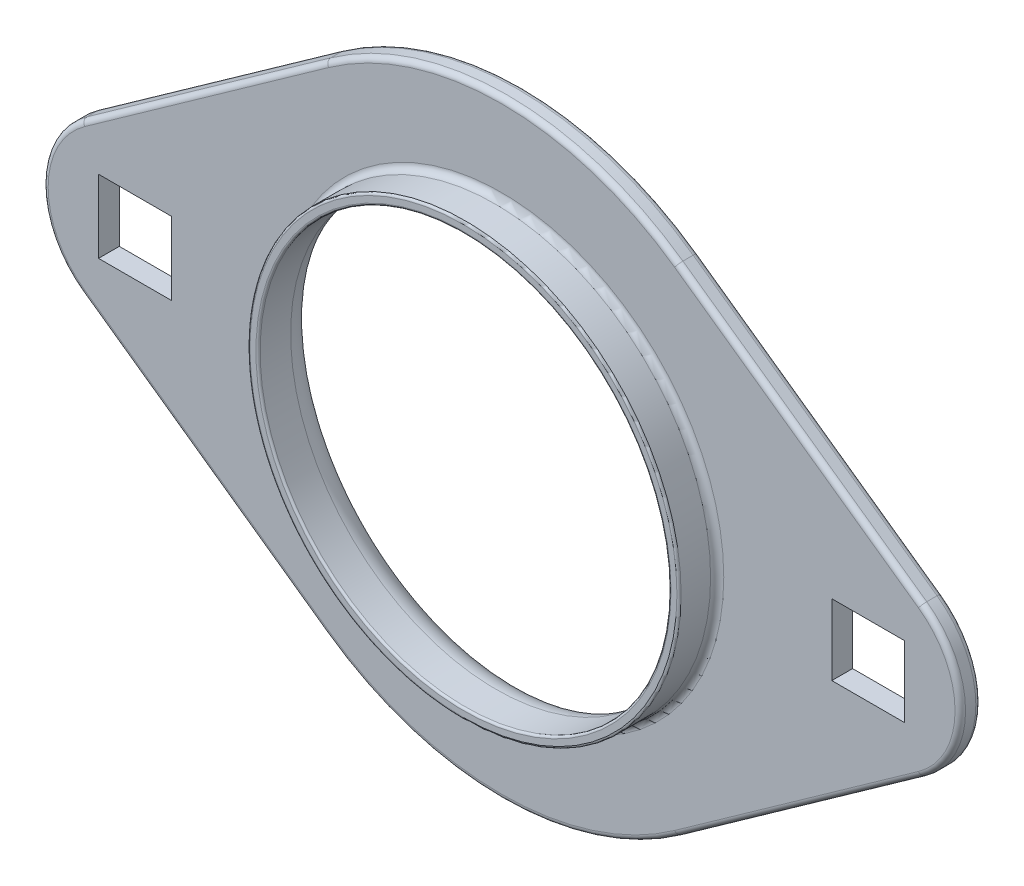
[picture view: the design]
ISO-10303-21;
HEADER;
FILE_DESCRIPTION(('STEP AP214'),'2;1');
FILE_NAME('part.step','',(''),(''),'','','');
FILE_SCHEMA(('AUTOMOTIVE_DESIGN { 1 0 10303 214 1 1 1 1 }'));
ENDSEC;
DATA;
#1=APPLICATION_CONTEXT('core data for automotive mechanical design processes');
#2=APPLICATION_PROTOCOL_DEFINITION('international standard','automotive_design',2000,#1);
#3=PRODUCT_CONTEXT('',#1,'mechanical');
#4=PRODUCT('Part','Part','',(#3));
#5=PRODUCT_RELATED_PRODUCT_CATEGORY('part','',(#4));
#6=PRODUCT_DEFINITION_FORMATION('','',#4);
#7=PRODUCT_DEFINITION_CONTEXT('part definition',#1,'design');
#8=PRODUCT_DEFINITION('design','',#6,#7);
#9=PRODUCT_DEFINITION_SHAPE('','',#8);
#10=(LENGTH_UNIT() NAMED_UNIT(*) SI_UNIT(.MILLI.,.METRE.));
#11=(NAMED_UNIT(*) PLANE_ANGLE_UNIT() SI_UNIT($,.RADIAN.));
#12=(NAMED_UNIT(*) SI_UNIT($,.STERADIAN.) SOLID_ANGLE_UNIT());
#13=UNCERTAINTY_MEASURE_WITH_UNIT(LENGTH_MEASURE(1.E-05),#10,'distance_accuracy_value','');
#14=(GEOMETRIC_REPRESENTATION_CONTEXT(3) GLOBAL_UNCERTAINTY_ASSIGNED_CONTEXT((#13)) GLOBAL_UNIT_ASSIGNED_CONTEXT((#10,
#11,#12)) REPRESENTATION_CONTEXT('',''));
#15=CARTESIAN_POINT('',(0.,0.,0.));
#16=DIRECTION('',(0.,0.,1.));
#17=DIRECTION('',(1.,0.,0.));
#18=AXIS2_PLACEMENT_3D('',#15,#16,#17);
#19=CARTESIAN_POINT('',(0.,0.,1.0033));
#20=DIRECTION('',(0.,0.,1.));
#21=DIRECTION('',(1.,0.,0.));
#22=AXIS2_PLACEMENT_3D('',#19,#20,#21);
#23=PLANE('',#22);
#24=CARTESIAN_POINT('',(35.39871,0.,1.0033));
#25=DIRECTION('',(0.,0.,1.));
#26=DIRECTION('',(1.,0.,0.));
#27=AXIS2_PLACEMENT_3D('',#24,#25,#26);
#28=CIRCLE('',#27,8.38200000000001);
#29=CARTESIAN_POINT('',(40.2493417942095,-6.83588291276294,1.0033));
#30=VERTEX_POINT('',#29);
#31=CARTESIAN_POINT('',(40.2493417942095,6.83588291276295,1.0033));
#32=VERTEX_POINT('',#31);
#33=EDGE_CURVE('E57',#30,#32,#28,.T.);
#34=ORIENTED_EDGE('',*,*,#33,.T.);
#35=DIRECTION('',(-0.81554317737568,0.578696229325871,0.));
#36=VECTOR('',#35,1.);
#37=CARTESIAN_POINT('',(16.7052819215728,23.5423664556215,1.0033));
#38=LINE('',#37,#36);
#39=CARTESIAN_POINT('',(16.7052819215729,23.5423664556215,1.0033));
#40=VERTEX_POINT('',#39);
#41=EDGE_CURVE('E372',#32,#40,#38,.T.);
#42=ORIENTED_EDGE('',*,*,#41,.T.);
#43=CARTESIAN_POINT('',(0.,0.,1.0033));
#44=DIRECTION('',(0.,0.,1.));
#45=DIRECTION('',(1.,0.,0.));
#46=AXIS2_PLACEMENT_3D('',#43,#44,#45);
#47=CIRCLE('',#46,28.8671);
#48=CARTESIAN_POINT('',(-16.7052819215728,23.5423664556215,1.0033));
#49=VERTEX_POINT('',#48);
#50=EDGE_CURVE('E360',#40,#49,#47,.T.);
#51=ORIENTED_EDGE('',*,*,#50,.T.);
#52=DIRECTION('',(-0.81554317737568,-0.578696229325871,0.));
#53=VECTOR('',#52,1.);
#54=CARTESIAN_POINT('',(-40.2493417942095,6.83588291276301,1.0033));
#55=LINE('',#54,#53);
#56=CARTESIAN_POINT('',(-40.2493417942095,6.83588291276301,1.0033));
#57=VERTEX_POINT('',#56);
#58=EDGE_CURVE('E362',#49,#57,#55,.T.);
#59=ORIENTED_EDGE('',*,*,#58,.T.);
#60=CARTESIAN_POINT('',(-35.39871,0.,1.0033));
#61=DIRECTION('',(0.,0.,1.));
#62=DIRECTION('',(1.,0.,0.));
#63=AXIS2_PLACEMENT_3D('',#60,#61,#62);
#64=CIRCLE('',#63,8.382);
#65=CARTESIAN_POINT('',(-40.2493417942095,-6.83588291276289,1.0033));
#66=VERTEX_POINT('',#65);
#67=EDGE_CURVE('E364',#57,#66,#64,.T.);
#68=ORIENTED_EDGE('',*,*,#67,.T.);
#69=DIRECTION('',(0.815543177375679,-0.578696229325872,0.));
#70=VECTOR('',#69,1.);
#71=CARTESIAN_POINT('',(-16.7052819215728,-23.5423664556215,1.0033));
#72=LINE('',#71,#70);
#73=CARTESIAN_POINT('',(-16.7052819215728,-23.5423664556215,1.0033));
#74=VERTEX_POINT('',#73);
#75=EDGE_CURVE('E366',#66,#74,#72,.T.);
#76=ORIENTED_EDGE('',*,*,#75,.T.);
#77=CARTESIAN_POINT('',(0.,0.,1.0033));
#78=DIRECTION('',(0.,0.,1.));
#79=DIRECTION('',(1.,0.,0.));
#80=AXIS2_PLACEMENT_3D('',#77,#78,#79);
#81=CIRCLE('',#80,28.8671);
#82=CARTESIAN_POINT('',(16.7052819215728,-23.5423664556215,1.0033));
#83=VERTEX_POINT('',#82);
#84=EDGE_CURVE('E368',#74,#83,#81,.T.);
#85=ORIENTED_EDGE('',*,*,#84,.T.);
#86=DIRECTION('',(0.81554317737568,0.578696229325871,0.));
#87=VECTOR('',#86,1.);
#88=CARTESIAN_POINT('',(40.2493417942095,-6.83588291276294,1.0033));
#89=LINE('',#88,#87);
#90=EDGE_CURVE('E62',#83,#30,#89,.T.);
#91=ORIENTED_EDGE('',*,*,#90,.T.);
#92=EDGE_LOOP('',(#34,#42,#51,#59,#68,#76,#85,#91));
#93=FACE_BOUND('',#92,.T.);
#94=CARTESIAN_POINT('',(0.,0.,1.0033));
#95=DIRECTION('',(0.,0.,1.));
#96=DIRECTION('',(1.,0.,0.));
#97=AXIS2_PLACEMENT_3D('',#94,#95,#96);
#98=CIRCLE('',#97,21.4503);
#99=CARTESIAN_POINT('',(21.4503,0.,1.0033));
#100=VERTEX_POINT('',#99);
#101=EDGE_CURVE('E310',#100,#100,#98,.F.);
#102=ORIENTED_EDGE('',*,*,#101,.T.);
#103=EDGE_LOOP('',(#102));
#104=FACE_BOUND('',#103,.T.);
#105=DIRECTION('',(1.,0.,0.));
#106=VECTOR('',#105,1.);
#107=CARTESIAN_POINT('',(31.88208,-3.42392,1.0033));
#108=LINE('',#107,#106);
#109=CARTESIAN_POINT('',(31.88208,-3.42392,1.0033));
#110=VERTEX_POINT('',#109);
#111=CARTESIAN_POINT('',(38.91788,-3.42392,1.0033));
#112=VERTEX_POINT('',#111);
#113=EDGE_CURVE('E214',#110,#112,#108,.T.);
#114=ORIENTED_EDGE('',*,*,#113,.F.);
#115=DIRECTION('',(0.,-1.,0.));
#116=VECTOR('',#115,1.);
#117=CARTESIAN_POINT('',(31.88208,3.42392,1.0033));
#118=LINE('',#117,#116);
#119=CARTESIAN_POINT('',(31.88208,3.42392,1.0033));
#120=VERTEX_POINT('',#119);
#121=EDGE_CURVE('E204',#120,#110,#118,.T.);
#122=ORIENTED_EDGE('',*,*,#121,.F.);
#123=DIRECTION('',(-1.,0.,0.));
#124=VECTOR('',#123,1.);
#125=CARTESIAN_POINT('',(31.88208,3.42392,1.0033));
#126=LINE('',#125,#124);
#127=CARTESIAN_POINT('',(38.91788,3.42392,1.0033));
#128=VERTEX_POINT('',#127);
#129=EDGE_CURVE('E230',#128,#120,#126,.T.);
#130=ORIENTED_EDGE('',*,*,#129,.F.);
#131=DIRECTION('',(0.,1.,0.));
#132=VECTOR('',#131,1.);
#133=CARTESIAN_POINT('',(38.91788,3.42392,1.0033));
#134=LINE('',#133,#132);
#135=EDGE_CURVE('E228',#112,#128,#134,.T.);
#136=ORIENTED_EDGE('',*,*,#135,.F.);
#137=EDGE_LOOP('',(#114,#122,#130,#136));
#138=FACE_BOUND('',#137,.T.);
#139=DIRECTION('',(1.,0.,0.));
#140=VECTOR('',#139,1.);
#141=CARTESIAN_POINT('',(-38.91788,-3.5179,1.0033));
#142=LINE('',#141,#140);
#143=CARTESIAN_POINT('',(-38.91788,-3.5179,1.0033));
#144=VERTEX_POINT('',#143);
#145=CARTESIAN_POINT('',(-31.88208,-3.5179,1.0033));
#146=VERTEX_POINT('',#145);
#147=EDGE_CURVE('E249',#144,#146,#142,.T.);
#148=ORIENTED_EDGE('',*,*,#147,.F.);
#149=DIRECTION('',(0.,-1.,0.));
#150=VECTOR('',#149,1.);
#151=CARTESIAN_POINT('',(-38.91788,3.5179,1.0033));
#152=LINE('',#151,#150);
#153=CARTESIAN_POINT('',(-38.91788,3.5179,1.0033));
#154=VERTEX_POINT('',#153);
#155=EDGE_CURVE('E247',#154,#144,#152,.T.);
#156=ORIENTED_EDGE('',*,*,#155,.F.);
#157=DIRECTION('',(-1.,0.,0.));
#158=VECTOR('',#157,1.);
#159=CARTESIAN_POINT('',(-38.91788,3.5179,1.0033));
#160=LINE('',#159,#158);
#161=CARTESIAN_POINT('',(-31.88208,3.5179,1.0033));
#162=VERTEX_POINT('',#161);
#163=EDGE_CURVE('E255',#162,#154,#160,.T.);
#164=ORIENTED_EDGE('',*,*,#163,.F.);
#165=DIRECTION('',(0.,1.,0.));
#166=VECTOR('',#165,1.);
#167=CARTESIAN_POINT('',(-31.88208,3.5179,1.0033));
#168=LINE('',#167,#166);
#169=EDGE_CURVE('E252',#146,#162,#168,.T.);
#170=ORIENTED_EDGE('',*,*,#169,.F.);
#171=EDGE_LOOP('',(#148,#156,#164,#170));
#172=FACE_BOUND('',#171,.T.);
#173=ADVANCED_FACE('F42',(#93,#104,#138,#172),#23,.T.);
#174=CARTESIAN_POINT('',(0.,0.,-1.0033));
#175=DIRECTION('',(0.,0.,1.));
#176=DIRECTION('',(1.,0.,0.));
#177=AXIS2_PLACEMENT_3D('',#174,#175,#176);
#178=PLANE('',#177);
#179=CARTESIAN_POINT('',(0.,0.,-1.0033));
#180=DIRECTION('',(0.,0.,1.));
#181=DIRECTION('',(1.,0.,0.));
#182=AXIS2_PLACEMENT_3D('',#179,#180,#181);
#183=CIRCLE('',#182,28.8671);
#184=CARTESIAN_POINT('',(-16.7052819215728,23.5423664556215,-1.0033));
#185=VERTEX_POINT('',#184);
#186=CARTESIAN_POINT('',(16.7052819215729,23.5423664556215,-1.0033));
#187=VERTEX_POINT('',#186);
#188=EDGE_CURVE('E319',#185,#187,#183,.F.);
#189=ORIENTED_EDGE('',*,*,#188,.T.);
#190=DIRECTION('',(-0.81554317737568,0.578696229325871,0.));
#191=VECTOR('',#190,1.);
#192=CARTESIAN_POINT('',(16.7052819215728,23.5423664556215,-1.0033));
#193=LINE('',#192,#191);
#194=CARTESIAN_POINT('',(40.2493417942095,6.83588291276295,-1.0033));
#195=VERTEX_POINT('',#194);
#196=EDGE_CURVE('E333',#187,#195,#193,.F.);
#197=ORIENTED_EDGE('',*,*,#196,.T.);
#198=CARTESIAN_POINT('',(35.39871,0.,-1.0033));
#199=DIRECTION('',(0.,0.,1.));
#200=DIRECTION('',(1.,0.,0.));
#201=AXIS2_PLACEMENT_3D('',#198,#199,#200);
#202=CIRCLE('',#201,8.38200000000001);
#203=CARTESIAN_POINT('',(40.2493417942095,-6.83588291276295,-1.0033));
#204=VERTEX_POINT('',#203);
#205=EDGE_CURVE('E331',#195,#204,#202,.F.);
#206=ORIENTED_EDGE('',*,*,#205,.T.);
#207=DIRECTION('',(0.81554317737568,0.578696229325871,0.));
#208=VECTOR('',#207,1.);
#209=CARTESIAN_POINT('',(16.7052819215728,-23.5423664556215,-1.0033));
#210=LINE('',#209,#208);
#211=CARTESIAN_POINT('',(16.7052819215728,-23.5423664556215,-1.0033));
#212=VERTEX_POINT('',#211);
#213=EDGE_CURVE('E329',#204,#212,#210,.F.);
#214=ORIENTED_EDGE('',*,*,#213,.T.);
#215=CARTESIAN_POINT('',(0.,0.,-1.0033));
#216=DIRECTION('',(0.,0.,1.));
#217=DIRECTION('',(1.,0.,0.));
#218=AXIS2_PLACEMENT_3D('',#215,#216,#217);
#219=CIRCLE('',#218,28.8671);
#220=CARTESIAN_POINT('',(-16.7052819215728,-23.5423664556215,-1.0033));
#221=VERTEX_POINT('',#220);
#222=EDGE_CURVE('E327',#212,#221,#219,.F.);
#223=ORIENTED_EDGE('',*,*,#222,.T.);
#224=DIRECTION('',(0.815543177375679,-0.578696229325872,0.));
#225=VECTOR('',#224,1.);
#226=CARTESIAN_POINT('',(-16.7052819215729,-23.5423664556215,-1.0033));
#227=LINE('',#226,#225);
#228=CARTESIAN_POINT('',(-40.2493417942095,-6.83588291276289,-1.0033));
#229=VERTEX_POINT('',#228);
#230=EDGE_CURVE('E325',#221,#229,#227,.F.);
#231=ORIENTED_EDGE('',*,*,#230,.T.);
#232=CARTESIAN_POINT('',(-35.39871,0.,-1.0033));
#233=DIRECTION('',(0.,0.,1.));
#234=DIRECTION('',(1.,0.,0.));
#235=AXIS2_PLACEMENT_3D('',#232,#233,#234);
#236=CIRCLE('',#235,8.382);
#237=CARTESIAN_POINT('',(-40.2493417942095,6.83588291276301,-1.0033));
#238=VERTEX_POINT('',#237);
#239=EDGE_CURVE('E323',#229,#238,#236,.F.);
#240=ORIENTED_EDGE('',*,*,#239,.T.);
#241=DIRECTION('',(-0.81554317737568,-0.578696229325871,0.));
#242=VECTOR('',#241,1.);
#243=CARTESIAN_POINT('',(-16.7052819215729,23.5423664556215,-1.0033));
#244=LINE('',#243,#242);
#245=EDGE_CURVE('E321',#238,#185,#244,.F.);
#246=ORIENTED_EDGE('',*,*,#245,.T.);
#247=EDGE_LOOP('',(#189,#197,#206,#214,#223,#231,#240,#246));
#248=FACE_BOUND('',#247,.T.);
#249=CARTESIAN_POINT('',(0.,0.,-1.0033));
#250=DIRECTION('',(0.,0.,1.));
#251=DIRECTION('',(1.,0.,0.));
#252=AXIS2_PLACEMENT_3D('',#249,#250,#251);
#253=CIRCLE('',#252,22.3774);
#254=CARTESIAN_POINT('',(22.3774,0.,-1.0033));
#255=VERTEX_POINT('',#254);
#256=EDGE_CURVE('E301',#255,#255,#253,.T.);
#257=ORIENTED_EDGE('',*,*,#256,.T.);
#258=EDGE_LOOP('',(#257));
#259=FACE_BOUND('',#258,.T.);
#260=DIRECTION('',(0.,-1.,0.));
#261=VECTOR('',#260,1.);
#262=CARTESIAN_POINT('',(-38.91788,3.5179,-1.0033));
#263=LINE('',#262,#261);
#264=CARTESIAN_POINT('',(-38.91788,3.5179,-1.0033));
#265=VERTEX_POINT('',#264);
#266=CARTESIAN_POINT('',(-38.91788,-3.5179,-1.0033));
#267=VERTEX_POINT('',#266);
#268=EDGE_CURVE('E222',#265,#267,#263,.T.);
#269=ORIENTED_EDGE('',*,*,#268,.T.);
#270=DIRECTION('',(1.,0.,0.));
#271=VECTOR('',#270,1.);
#272=CARTESIAN_POINT('',(-38.91788,-3.5179,-1.0033));
#273=LINE('',#272,#271);
#274=CARTESIAN_POINT('',(-31.88208,-3.5179,-1.0033));
#275=VERTEX_POINT('',#274);
#276=EDGE_CURVE('E260',#267,#275,#273,.T.);
#277=ORIENTED_EDGE('',*,*,#276,.T.);
#278=DIRECTION('',(0.,1.,0.));
#279=VECTOR('',#278,1.);
#280=CARTESIAN_POINT('',(-31.88208,3.5179,-1.0033));
#281=LINE('',#280,#279);
#282=CARTESIAN_POINT('',(-31.88208,3.5179,-1.0033));
#283=VERTEX_POINT('',#282);
#284=EDGE_CURVE('E263',#275,#283,#281,.T.);
#285=ORIENTED_EDGE('',*,*,#284,.T.);
#286=DIRECTION('',(-1.,0.,0.));
#287=VECTOR('',#286,1.);
#288=CARTESIAN_POINT('',(-38.91788,3.5179,-1.0033));
#289=LINE('',#288,#287);
#290=EDGE_CURVE('E250',#283,#265,#289,.T.);
#291=ORIENTED_EDGE('',*,*,#290,.T.);
#292=EDGE_LOOP('',(#269,#277,#285,#291));
#293=FACE_BOUND('',#292,.T.);
#294=DIRECTION('',(0.,-1.,0.));
#295=VECTOR('',#294,1.);
#296=CARTESIAN_POINT('',(31.88208,3.42392,-1.0033));
#297=LINE('',#296,#295);
#298=CARTESIAN_POINT('',(31.88208,3.42392,-1.0033));
#299=VERTEX_POINT('',#298);
#300=CARTESIAN_POINT('',(31.88208,-3.42392,-1.0033));
#301=VERTEX_POINT('',#300);
#302=EDGE_CURVE('E234',#299,#301,#297,.T.);
#303=ORIENTED_EDGE('',*,*,#302,.T.);
#304=DIRECTION('',(1.,0.,0.));
#305=VECTOR('',#304,1.);
#306=CARTESIAN_POINT('',(31.88208,-3.42392,-1.0033));
#307=LINE('',#306,#305);
#308=CARTESIAN_POINT('',(38.91788,-3.42392,-1.0033));
#309=VERTEX_POINT('',#308);
#310=EDGE_CURVE('E221',#301,#309,#307,.T.);
#311=ORIENTED_EDGE('',*,*,#310,.T.);
#312=DIRECTION('',(0.,1.,0.));
#313=VECTOR('',#312,1.);
#314=CARTESIAN_POINT('',(38.91788,3.42392,-1.0033));
#315=LINE('',#314,#313);
#316=CARTESIAN_POINT('',(38.91788,3.42392,-1.0033));
#317=VERTEX_POINT('',#316);
#318=EDGE_CURVE('E238',#309,#317,#315,.T.);
#319=ORIENTED_EDGE('',*,*,#318,.T.);
#320=DIRECTION('',(-1.,0.,0.));
#321=VECTOR('',#320,1.);
#322=CARTESIAN_POINT('',(31.88208,3.42392,-1.0033));
#323=LINE('',#322,#321);
#324=EDGE_CURVE('E215',#317,#299,#323,.T.);
#325=ORIENTED_EDGE('',*,*,#324,.T.);
#326=EDGE_LOOP('',(#303,#311,#319,#325));
#327=FACE_BOUND('',#326,.T.);
#328=ADVANCED_FACE('F464',(#248,#259,#293,#327),#178,.F.);
#329=CARTESIAN_POINT('',(0.,0.,1.0033));
#330=DIRECTION('',(0.,0.,-1.));
#331=DIRECTION('',(-1.,0.,0.));
#332=AXIS2_PLACEMENT_3D('',#329,#330,#331);
#333=CYLINDRICAL_SURFACE('',#332,29.3751);
#334=DIRECTION('',(0.,0.,-1.));
#335=VECTOR('',#334,1.);
#336=CARTESIAN_POINT('',(16.9992596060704,23.9566623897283,1.0033));
#337=LINE('',#336,#335);
#338=CARTESIAN_POINT('',(16.9992596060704,23.9566623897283,0.4953));
#339=VERTEX_POINT('',#338);
#340=CARTESIAN_POINT('',(16.9992596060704,23.9566623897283,-0.4953));
#341=VERTEX_POINT('',#340);
#342=EDGE_CURVE('E277',#339,#341,#337,.T.);
#343=ORIENTED_EDGE('',*,*,#342,.T.);
#344=CARTESIAN_POINT('',(0.,0.,-0.4953));
#345=DIRECTION('',(0.,0.,1.));
#346=DIRECTION('',(1.,0.,0.));
#347=AXIS2_PLACEMENT_3D('',#344,#345,#346);
#348=CIRCLE('',#347,29.3751);
#349=CARTESIAN_POINT('',(-16.9992596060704,23.9566623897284,-0.4953));
#350=VERTEX_POINT('',#349);
#351=EDGE_CURVE('E376',#341,#350,#348,.T.);
#352=ORIENTED_EDGE('',*,*,#351,.T.);
#353=DIRECTION('',(0.,0.,-1.));
#354=VECTOR('',#353,1.);
#355=CARTESIAN_POINT('',(-16.9992596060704,23.9566623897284,1.0033));
#356=LINE('',#355,#354);
#357=CARTESIAN_POINT('',(-16.9992596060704,23.9566623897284,0.4953));
#358=VERTEX_POINT('',#357);
#359=EDGE_CURVE('E298',#358,#350,#356,.T.);
#360=ORIENTED_EDGE('',*,*,#359,.F.);
#361=CARTESIAN_POINT('',(0.,0.,0.4953));
#362=DIRECTION('',(0.,0.,1.));
#363=DIRECTION('',(1.,0.,0.));
#364=AXIS2_PLACEMENT_3D('',#361,#362,#363);
#365=CIRCLE('',#364,29.3751);
#366=EDGE_CURVE('E374',#358,#339,#365,.F.);
#367=ORIENTED_EDGE('',*,*,#366,.T.);
#368=EDGE_LOOP('',(#343,#352,#360,#367));
#369=FACE_BOUND('',#368,.T.);
#370=ADVANCED_FACE('F467',(#369),#333,.T.);
#371=CARTESIAN_POINT('',(-16.9992596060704,23.9566623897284,1.0033));
#372=DIRECTION('',(0.578696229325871,-0.81554317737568,0.));
#373=DIRECTION('',(0.81554317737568,0.578696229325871,0.));
#374=AXIS2_PLACEMENT_3D('',#371,#372,#373);
#375=PLANE('',#374);
#376=ORIENTED_EDGE('',*,*,#359,.T.);
#377=DIRECTION('',(-0.81554317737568,-0.578696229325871,0.));
#378=VECTOR('',#377,1.);
#379=CARTESIAN_POINT('',(-16.9992596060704,23.9566623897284,-0.4953));
#380=LINE('',#379,#378);
#381=CARTESIAN_POINT('',(-40.543319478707,7.25017884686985,-0.4953));
#382=VERTEX_POINT('',#381);
#383=EDGE_CURVE('E358',#350,#382,#380,.T.);
#384=ORIENTED_EDGE('',*,*,#383,.T.);
#385=DIRECTION('',(0.,0.,-1.));
#386=VECTOR('',#385,1.);
#387=CARTESIAN_POINT('',(-40.543319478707,7.25017884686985,1.0033));
#388=LINE('',#387,#386);
#389=CARTESIAN_POINT('',(-40.543319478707,7.25017884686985,0.4953));
#390=VERTEX_POINT('',#389);
#391=EDGE_CURVE('E295',#390,#382,#388,.T.);
#392=ORIENTED_EDGE('',*,*,#391,.F.);
#393=DIRECTION('',(-0.81554317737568,-0.578696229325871,0.));
#394=VECTOR('',#393,1.);
#395=CARTESIAN_POINT('',(-16.9992596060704,23.9566623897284,0.4953));
#396=LINE('',#395,#394);
#397=EDGE_CURVE('E356',#390,#358,#396,.F.);
#398=ORIENTED_EDGE('',*,*,#397,.T.);
#399=EDGE_LOOP('',(#376,#384,#392,#398));
#400=FACE_BOUND('',#399,.T.);
#401=ADVANCED_FACE('F513',(#400),#375,.F.);
#402=CARTESIAN_POINT('',(-35.39871,0.,1.0033));
#403=DIRECTION('',(0.,0.,-1.));
#404=DIRECTION('',(-1.,0.,0.));
#405=AXIS2_PLACEMENT_3D('',#402,#403,#404);
#406=CYLINDRICAL_SURFACE('',#405,8.89);
#407=ORIENTED_EDGE('',*,*,#391,.T.);
#408=CARTESIAN_POINT('',(-35.39871,0.,-0.4953));
#409=DIRECTION('',(0.,0.,1.));
#410=DIRECTION('',(1.,0.,0.));
#411=AXIS2_PLACEMENT_3D('',#408,#409,#410);
#412=CIRCLE('',#411,8.89);
#413=CARTESIAN_POINT('',(-40.543319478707,-7.25017884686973,-0.4953));
#414=VERTEX_POINT('',#413);
#415=EDGE_CURVE('E354',#382,#414,#412,.T.);
#416=ORIENTED_EDGE('',*,*,#415,.T.);
#417=DIRECTION('',(0.,0.,-1.));
#418=VECTOR('',#417,1.);
#419=CARTESIAN_POINT('',(-40.543319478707,-7.25017884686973,1.0033));
#420=LINE('',#419,#418);
#421=CARTESIAN_POINT('',(-40.543319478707,-7.25017884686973,0.4953));
#422=VERTEX_POINT('',#421);
#423=EDGE_CURVE('E292',#422,#414,#420,.T.);
#424=ORIENTED_EDGE('',*,*,#423,.F.);
#425=CARTESIAN_POINT('',(-35.39871,0.,0.4953));
#426=DIRECTION('',(0.,0.,1.));
#427=DIRECTION('',(1.,0.,0.));
#428=AXIS2_PLACEMENT_3D('',#425,#426,#427);
#429=CIRCLE('',#428,8.89);
#430=EDGE_CURVE('E352',#422,#390,#429,.F.);
#431=ORIENTED_EDGE('',*,*,#430,.T.);
#432=EDGE_LOOP('',(#407,#416,#424,#431));
#433=FACE_BOUND('',#432,.T.);
#434=ADVANCED_FACE('F509',(#433),#406,.T.);
#435=CARTESIAN_POINT('',(-16.9992596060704,-23.9566623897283,1.0033));
#436=DIRECTION('',(0.578696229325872,0.815543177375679,0.));
#437=DIRECTION('',(-0.815543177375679,0.578696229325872,0.));
#438=AXIS2_PLACEMENT_3D('',#435,#436,#437);
#439=PLANE('',#438);
#440=ORIENTED_EDGE('',*,*,#423,.T.);
#441=DIRECTION('',(0.815543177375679,-0.578696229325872,0.));
#442=VECTOR('',#441,1.);
#443=CARTESIAN_POINT('',(-16.9992596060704,-23.9566623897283,-0.4953));
#444=LINE('',#443,#442);
#445=CARTESIAN_POINT('',(-16.9992596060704,-23.9566623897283,-0.4953));
#446=VERTEX_POINT('',#445);
#447=EDGE_CURVE('E350',#414,#446,#444,.T.);
#448=ORIENTED_EDGE('',*,*,#447,.T.);
#449=DIRECTION('',(0.,0.,-1.));
#450=VECTOR('',#449,1.);
#451=CARTESIAN_POINT('',(-16.9992596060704,-23.9566623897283,1.0033));
#452=LINE('',#451,#450);
#453=CARTESIAN_POINT('',(-16.9992596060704,-23.9566623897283,0.4953));
#454=VERTEX_POINT('',#453);
#455=EDGE_CURVE('E289',#454,#446,#452,.T.);
#456=ORIENTED_EDGE('',*,*,#455,.F.);
#457=DIRECTION('',(0.815543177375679,-0.578696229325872,0.));
#458=VECTOR('',#457,1.);
#459=CARTESIAN_POINT('',(-40.543319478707,-7.25017884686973,0.4953));
#460=LINE('',#459,#458);
#461=EDGE_CURVE('E348',#454,#422,#460,.F.);
#462=ORIENTED_EDGE('',*,*,#461,.T.);
#463=EDGE_LOOP('',(#440,#448,#456,#462));
#464=FACE_BOUND('',#463,.T.);
#465=ADVANCED_FACE('F505',(#464),#439,.F.);
#466=CARTESIAN_POINT('',(0.,0.,1.0033));
#467=DIRECTION('',(0.,0.,-1.));
#468=DIRECTION('',(-1.,0.,0.));
#469=AXIS2_PLACEMENT_3D('',#466,#467,#468);
#470=CYLINDRICAL_SURFACE('',#469,29.3751);
#471=ORIENTED_EDGE('',*,*,#455,.T.);
#472=CARTESIAN_POINT('',(0.,0.,-0.4953));
#473=DIRECTION('',(0.,0.,1.));
#474=DIRECTION('',(1.,0.,0.));
#475=AXIS2_PLACEMENT_3D('',#472,#473,#474);
#476=CIRCLE('',#475,29.3751);
#477=CARTESIAN_POINT('',(16.9992596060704,-23.9566623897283,-0.4953));
#478=VERTEX_POINT('',#477);
#479=EDGE_CURVE('E346',#446,#478,#476,.T.);
#480=ORIENTED_EDGE('',*,*,#479,.T.);
#481=DIRECTION('',(0.,0.,-1.));
#482=VECTOR('',#481,1.);
#483=CARTESIAN_POINT('',(16.9992596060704,-23.9566623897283,1.0033));
#484=LINE('',#483,#482);
#485=CARTESIAN_POINT('',(16.9992596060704,-23.9566623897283,0.4953));
#486=VERTEX_POINT('',#485);
#487=EDGE_CURVE('E286',#486,#478,#484,.T.);
#488=ORIENTED_EDGE('',*,*,#487,.F.);
#489=CARTESIAN_POINT('',(0.,0.,0.4953));
#490=DIRECTION('',(0.,0.,1.));
#491=DIRECTION('',(1.,0.,0.));
#492=AXIS2_PLACEMENT_3D('',#489,#490,#491);
#493=CIRCLE('',#492,29.3751);
#494=EDGE_CURVE('E344',#486,#454,#493,.F.);
#495=ORIENTED_EDGE('',*,*,#494,.T.);
#496=EDGE_LOOP('',(#471,#480,#488,#495));
#497=FACE_BOUND('',#496,.T.);
#498=ADVANCED_FACE('F501',(#497),#470,.T.);
#499=CARTESIAN_POINT('',(16.9992596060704,-23.9566623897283,1.0033));
#500=DIRECTION('',(-0.578696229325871,0.815543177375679,0.));
#501=DIRECTION('',(-0.81554317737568,-0.578696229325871,0.));
#502=AXIS2_PLACEMENT_3D('',#499,#500,#501);
#503=PLANE('',#502);
#504=ORIENTED_EDGE('',*,*,#487,.T.);
#505=DIRECTION('',(0.81554317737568,0.578696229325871,0.));
#506=VECTOR('',#505,1.);
#507=CARTESIAN_POINT('',(16.9992596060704,-23.9566623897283,-0.4953));
#508=LINE('',#507,#506);
#509=CARTESIAN_POINT('',(40.543319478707,-7.25017884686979,-0.4953));
#510=VERTEX_POINT('',#509);
#511=EDGE_CURVE('E342',#478,#510,#508,.T.);
#512=ORIENTED_EDGE('',*,*,#511,.T.);
#513=DIRECTION('',(0.,0.,-1.));
#514=VECTOR('',#513,1.);
#515=CARTESIAN_POINT('',(40.543319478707,-7.25017884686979,1.0033));
#516=LINE('',#515,#514);
#517=CARTESIAN_POINT('',(40.543319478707,-7.25017884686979,0.4953));
#518=VERTEX_POINT('',#517);
#519=EDGE_CURVE('E283',#518,#510,#516,.T.);
#520=ORIENTED_EDGE('',*,*,#519,.F.);
#521=DIRECTION('',(0.81554317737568,0.578696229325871,0.));
#522=VECTOR('',#521,1.);
#523=CARTESIAN_POINT('',(16.9992596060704,-23.9566623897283,0.4953));
#524=LINE('',#523,#522);
#525=EDGE_CURVE('E340',#518,#486,#524,.F.);
#526=ORIENTED_EDGE('',*,*,#525,.T.);
#527=EDGE_LOOP('',(#504,#512,#520,#526));
#528=FACE_BOUND('',#527,.T.);
#529=ADVANCED_FACE('F497',(#528),#503,.F.);
#530=CARTESIAN_POINT('',(35.39871,0.,1.0033));
#531=DIRECTION('',(0.,0.,-1.));
#532=DIRECTION('',(-1.,0.,0.));
#533=AXIS2_PLACEMENT_3D('',#530,#531,#532);
#534=CYLINDRICAL_SURFACE('',#533,8.89000000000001);
#535=ORIENTED_EDGE('',*,*,#519,.T.);
#536=CARTESIAN_POINT('',(35.39871,0.,-0.4953));
#537=DIRECTION('',(0.,0.,1.));
#538=DIRECTION('',(1.,0.,0.));
#539=AXIS2_PLACEMENT_3D('',#536,#537,#538);
#540=CIRCLE('',#539,8.89000000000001);
#541=CARTESIAN_POINT('',(40.543319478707,7.2501788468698,-0.4953));
#542=VERTEX_POINT('',#541);
#543=EDGE_CURVE('E338',#510,#542,#540,.T.);
#544=ORIENTED_EDGE('',*,*,#543,.T.);
#545=DIRECTION('',(0.,0.,-1.));
#546=VECTOR('',#545,1.);
#547=CARTESIAN_POINT('',(40.543319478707,7.2501788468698,1.0033));
#548=LINE('',#547,#546);
#549=CARTESIAN_POINT('',(40.543319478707,7.2501788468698,0.4953));
#550=VERTEX_POINT('',#549);
#551=EDGE_CURVE('E280',#550,#542,#548,.T.);
#552=ORIENTED_EDGE('',*,*,#551,.F.);
#553=CARTESIAN_POINT('',(35.39871,0.,0.4953));
#554=DIRECTION('',(0.,0.,1.));
#555=DIRECTION('',(1.,0.,0.));
#556=AXIS2_PLACEMENT_3D('',#553,#554,#555);
#557=CIRCLE('',#556,8.89000000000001);
#558=EDGE_CURVE('E336',#550,#518,#557,.F.);
#559=ORIENTED_EDGE('',*,*,#558,.T.);
#560=EDGE_LOOP('',(#535,#544,#552,#559));
#561=FACE_BOUND('',#560,.T.);
#562=ADVANCED_FACE('F493',(#561),#534,.T.);
#563=CARTESIAN_POINT('',(16.9992596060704,23.9566623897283,1.0033));
#564=DIRECTION('',(-0.578696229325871,-0.81554317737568,0.));
#565=DIRECTION('',(0.81554317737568,-0.578696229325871,0.));
#566=AXIS2_PLACEMENT_3D('',#563,#564,#565);
#567=PLANE('',#566);
#568=ORIENTED_EDGE('',*,*,#551,.T.);
#569=DIRECTION('',(-0.81554317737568,0.578696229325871,0.));
#570=VECTOR('',#569,1.);
#571=CARTESIAN_POINT('',(16.9992596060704,23.9566623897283,-0.4953));
#572=LINE('',#571,#570);
#573=EDGE_CURVE('E316',#542,#341,#572,.T.);
#574=ORIENTED_EDGE('',*,*,#573,.T.);
#575=ORIENTED_EDGE('',*,*,#342,.F.);
#576=DIRECTION('',(-0.81554317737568,0.578696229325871,0.));
#577=VECTOR('',#576,1.);
#578=CARTESIAN_POINT('',(40.543319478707,7.25017884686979,0.4953));
#579=LINE('',#578,#577);
#580=EDGE_CURVE('E313',#339,#550,#579,.F.);
#581=ORIENTED_EDGE('',*,*,#580,.T.);
#582=EDGE_LOOP('',(#568,#574,#575,#581));
#583=FACE_BOUND('',#582,.T.);
#584=ADVANCED_FACE('F453',(#583),#567,.F.);
#585=CARTESIAN_POINT('',(0.,0.,1.0033));
#586=DIRECTION('',(0.,0.,-1.));
#587=DIRECTION('',(-1.,0.,0.));
#588=AXIS2_PLACEMENT_3D('',#585,#586,#587);
#589=CYLINDRICAL_SURFACE('',#588,19.8374);
#590=CARTESIAN_POINT('',(0.,0.,4.4831));
#591=DIRECTION('',(0.,0.,1.));
#592=DIRECTION('',(1.,0.,0.));
#593=AXIS2_PLACEMENT_3D('',#590,#591,#592);
#594=CIRCLE('',#593,19.8374);
#595=CARTESIAN_POINT('',(19.8374,0.,4.4831));
#596=VERTEX_POINT('',#595);
#597=EDGE_CURVE('E13',#596,#596,#594,.T.);
#598=ORIENTED_EDGE('',*,*,#597,.T.);
#599=EDGE_LOOP('',(#598));
#600=FACE_BOUND('',#599,.T.);
#601=CARTESIAN_POINT('',(0.,0.,1.5367));
#602=DIRECTION('',(0.,0.,1.));
#603=DIRECTION('',(1.,0.,0.));
#604=AXIS2_PLACEMENT_3D('',#601,#602,#603);
#605=CIRCLE('',#604,19.8374);
#606=CARTESIAN_POINT('',(19.8374,0.,1.5367));
#607=VERTEX_POINT('',#606);
#608=EDGE_CURVE('E304',#607,#607,#605,.F.);
#609=ORIENTED_EDGE('',*,*,#608,.T.);
#610=EDGE_LOOP('',(#609));
#611=FACE_BOUND('',#610,.T.);
#612=ADVANCED_FACE('F449',(#600,#611),#589,.F.);
#613=CARTESIAN_POINT('',(-38.91788,3.5179,1.0033));
#614=DIRECTION('',(1.,0.,0.));
#615=DIRECTION('',(0.,1.,0.));
#616=AXIS2_PLACEMENT_3D('',#613,#614,#615);
#617=PLANE('',#616);
#618=ORIENTED_EDGE('',*,*,#268,.F.);
#619=DIRECTION('',(0.,0.,-1.));
#620=VECTOR('',#619,1.);
#621=CARTESIAN_POINT('',(-38.91788,3.5179,1.0033));
#622=LINE('',#621,#620);
#623=EDGE_CURVE('E257',#154,#265,#622,.T.);
#624=ORIENTED_EDGE('',*,*,#623,.F.);
#625=ORIENTED_EDGE('',*,*,#155,.T.);
#626=DIRECTION('',(0.,0.,-1.));
#627=VECTOR('',#626,1.);
#628=CARTESIAN_POINT('',(-38.91788,-3.5179,1.0033));
#629=LINE('',#628,#627);
#630=EDGE_CURVE('E274',#144,#267,#629,.T.);
#631=ORIENTED_EDGE('',*,*,#630,.T.);
#632=EDGE_LOOP('',(#618,#624,#625,#631));
#633=FACE_BOUND('',#632,.T.);
#634=ADVANCED_FACE('F452',(#633),#617,.T.);
#635=CARTESIAN_POINT('',(-38.91788,-3.5179,1.0033));
#636=DIRECTION('',(0.,1.,0.));
#637=DIRECTION('',(0.,0.,1.));
#638=AXIS2_PLACEMENT_3D('',#635,#636,#637);
#639=PLANE('',#638);
#640=ORIENTED_EDGE('',*,*,#276,.F.);
#641=ORIENTED_EDGE('',*,*,#630,.F.);
#642=ORIENTED_EDGE('',*,*,#147,.T.);
#643=DIRECTION('',(0.,0.,-1.));
#644=VECTOR('',#643,1.);
#645=CARTESIAN_POINT('',(-31.88208,-3.5179,1.0033));
#646=LINE('',#645,#644);
#647=EDGE_CURVE('E272',#146,#275,#646,.T.);
#648=ORIENTED_EDGE('',*,*,#647,.T.);
#649=EDGE_LOOP('',(#640,#641,#642,#648));
#650=FACE_BOUND('',#649,.T.);
#651=ADVANCED_FACE('F814',(#650),#639,.T.);
#652=CARTESIAN_POINT('',(-31.88208,3.5179,1.0033));
#653=DIRECTION('',(-1.,0.,0.));
#654=DIRECTION('',(0.,-1.,0.));
#655=AXIS2_PLACEMENT_3D('',#652,#653,#654);
#656=PLANE('',#655);
#657=ORIENTED_EDGE('',*,*,#284,.F.);
#658=ORIENTED_EDGE('',*,*,#647,.F.);
#659=ORIENTED_EDGE('',*,*,#169,.T.);
#660=DIRECTION('',(0.,0.,-1.));
#661=VECTOR('',#660,1.);
#662=CARTESIAN_POINT('',(-31.88208,3.5179,1.0033));
#663=LINE('',#662,#661);
#664=EDGE_CURVE('E270',#162,#283,#663,.T.);
#665=ORIENTED_EDGE('',*,*,#664,.T.);
#666=EDGE_LOOP('',(#657,#658,#659,#665));
#667=FACE_BOUND('',#666,.T.);
#668=ADVANCED_FACE('F805',(#667),#656,.T.);
#669=CARTESIAN_POINT('',(-38.91788,3.5179,1.0033));
#670=DIRECTION('',(0.,-1.,0.));
#671=DIRECTION('',(0.,0.,-1.));
#672=AXIS2_PLACEMENT_3D('',#669,#670,#671);
#673=PLANE('',#672);
#674=ORIENTED_EDGE('',*,*,#290,.F.);
#675=ORIENTED_EDGE('',*,*,#664,.F.);
#676=ORIENTED_EDGE('',*,*,#163,.T.);
#677=ORIENTED_EDGE('',*,*,#623,.T.);
#678=EDGE_LOOP('',(#674,#675,#676,#677));
#679=FACE_BOUND('',#678,.T.);
#680=ADVANCED_FACE('F797',(#679),#673,.T.);
#681=CARTESIAN_POINT('',(31.88208,3.42392,1.0033));
#682=DIRECTION('',(1.,0.,0.));
#683=DIRECTION('',(0.,0.,-1.));
#684=AXIS2_PLACEMENT_3D('',#681,#682,#683);
#685=PLANE('',#684);
#686=ORIENTED_EDGE('',*,*,#302,.F.);
#687=DIRECTION('',(0.,0.,-1.));
#688=VECTOR('',#687,1.);
#689=CARTESIAN_POINT('',(31.88208,3.42392,1.0033));
#690=LINE('',#689,#688);
#691=EDGE_CURVE('E210',#120,#299,#690,.T.);
#692=ORIENTED_EDGE('',*,*,#691,.F.);
#693=ORIENTED_EDGE('',*,*,#121,.T.);
#694=DIRECTION('',(0.,0.,-1.));
#695=VECTOR('',#694,1.);
#696=CARTESIAN_POINT('',(31.88208,-3.42392,1.0033));
#697=LINE('',#696,#695);
#698=EDGE_CURVE('E207',#110,#301,#697,.T.);
#699=ORIENTED_EDGE('',*,*,#698,.T.);
#700=EDGE_LOOP('',(#686,#692,#693,#699));
#701=FACE_BOUND('',#700,.T.);
#702=ADVANCED_FACE('F206',(#701),#685,.T.);
#703=CARTESIAN_POINT('',(31.88208,-3.42392,1.0033));
#704=DIRECTION('',(0.,1.,0.));
#705=DIRECTION('',(0.,0.,1.));
#706=AXIS2_PLACEMENT_3D('',#703,#704,#705);
#707=PLANE('',#706);
#708=ORIENTED_EDGE('',*,*,#310,.F.);
#709=ORIENTED_EDGE('',*,*,#698,.F.);
#710=ORIENTED_EDGE('',*,*,#113,.T.);
#711=DIRECTION('',(0.,0.,-1.));
#712=VECTOR('',#711,1.);
#713=CARTESIAN_POINT('',(38.91788,-3.42392,1.0033));
#714=LINE('',#713,#712);
#715=EDGE_CURVE('E223',#112,#309,#714,.T.);
#716=ORIENTED_EDGE('',*,*,#715,.T.);
#717=EDGE_LOOP('',(#708,#709,#710,#716));
#718=FACE_BOUND('',#717,.T.);
#719=ADVANCED_FACE('F218',(#718),#707,.T.);
#720=CARTESIAN_POINT('',(38.91788,3.42392,1.0033));
#721=DIRECTION('',(-1.,0.,0.));
#722=DIRECTION('',(0.,0.,1.));
#723=AXIS2_PLACEMENT_3D('',#720,#721,#722);
#724=PLANE('',#723);
#725=ORIENTED_EDGE('',*,*,#318,.F.);
#726=ORIENTED_EDGE('',*,*,#715,.F.);
#727=ORIENTED_EDGE('',*,*,#135,.T.);
#728=DIRECTION('',(0.,0.,-1.));
#729=VECTOR('',#728,1.);
#730=CARTESIAN_POINT('',(38.91788,3.42392,1.0033));
#731=LINE('',#730,#729);
#732=EDGE_CURVE('E244',#128,#317,#731,.T.);
#733=ORIENTED_EDGE('',*,*,#732,.T.);
#734=EDGE_LOOP('',(#725,#726,#727,#733));
#735=FACE_BOUND('',#734,.T.);
#736=ADVANCED_FACE('F475',(#735),#724,.T.);
#737=CARTESIAN_POINT('',(31.88208,3.42392,1.0033));
#738=DIRECTION('',(0.,-1.,0.));
#739=DIRECTION('',(0.,0.,-1.));
#740=AXIS2_PLACEMENT_3D('',#737,#738,#739);
#741=PLANE('',#740);
#742=ORIENTED_EDGE('',*,*,#324,.F.);
#743=ORIENTED_EDGE('',*,*,#732,.F.);
#744=ORIENTED_EDGE('',*,*,#129,.T.);
#745=ORIENTED_EDGE('',*,*,#691,.T.);
#746=EDGE_LOOP('',(#742,#743,#744,#745));
#747=FACE_BOUND('',#746,.T.);
#748=ADVANCED_FACE('F441',(#747),#741,.T.);
#749=CARTESIAN_POINT('',(0.,0.,4.6863));
#750=DIRECTION('',(0.,0.,1.));
#751=DIRECTION('',(1.,0.,0.));
#752=AXIS2_PLACEMENT_3D('',#749,#750,#751);
#753=PLANE('',#752);
#754=CARTESIAN_POINT('',(0.,0.,4.6863));
#755=DIRECTION('',(0.,0.,1.));
#756=DIRECTION('',(1.,0.,0.));
#757=AXIS2_PLACEMENT_3D('',#754,#755,#756);
#758=CIRCLE('',#757,20.6121);
#759=CARTESIAN_POINT('',(20.6121,0.,4.6863));
#760=VERTEX_POINT('',#759);
#761=EDGE_CURVE('E424',#760,#760,#758,.T.);
#762=ORIENTED_EDGE('',*,*,#761,.T.);
#763=EDGE_LOOP('',(#762));
#764=FACE_BOUND('',#763,.T.);
#765=CARTESIAN_POINT('',(0.,0.,4.6863));
#766=DIRECTION('',(0.,0.,1.));
#767=DIRECTION('',(1.,0.,0.));
#768=AXIS2_PLACEMENT_3D('',#765,#766,#767);
#769=CIRCLE('',#768,20.0406);
#770=CARTESIAN_POINT('',(20.0406,0.,4.6863));
#771=VERTEX_POINT('',#770);
#772=EDGE_CURVE('E378',#771,#771,#769,.F.);
#773=ORIENTED_EDGE('',*,*,#772,.T.);
#774=EDGE_LOOP('',(#773));
#775=FACE_BOUND('',#774,.T.);
#776=ADVANCED_FACE('F438',(#764,#775),#753,.T.);
#777=CARTESIAN_POINT('',(0.,0.,4.6863));
#778=DIRECTION('',(0.,0.,-1.));
#779=DIRECTION('',(-1.,0.,0.));
#780=AXIS2_PLACEMENT_3D('',#777,#778,#779);
#781=CYLINDRICAL_SURFACE('',#780,20.8153);
#782=CARTESIAN_POINT('',(0.,0.,4.4831));
#783=DIRECTION('',(0.,0.,1.));
#784=DIRECTION('',(1.,0.,0.));
#785=AXIS2_PLACEMENT_3D('',#782,#783,#784);
#786=CIRCLE('',#785,20.8153);
#787=CARTESIAN_POINT('',(20.8153,0.,4.4831));
#788=VERTEX_POINT('',#787);
#789=EDGE_CURVE('E50',#788,#788,#786,.F.);
#790=ORIENTED_EDGE('',*,*,#789,.T.);
#791=EDGE_LOOP('',(#790));
#792=FACE_BOUND('',#791,.T.);
#793=CARTESIAN_POINT('',(0.,0.,1.6383));
#794=DIRECTION('',(0.,0.,1.));
#795=DIRECTION('',(1.,0.,0.));
#796=AXIS2_PLACEMENT_3D('',#793,#794,#795);
#797=CIRCLE('',#796,20.8153);
#798=CARTESIAN_POINT('',(20.8153,0.,1.6383));
#799=VERTEX_POINT('',#798);
#800=EDGE_CURVE('E307',#799,#799,#797,.T.);
#801=ORIENTED_EDGE('',*,*,#800,.T.);
#802=EDGE_LOOP('',(#801));
#803=FACE_BOUND('',#802,.T.);
#804=ADVANCED_FACE('F429',(#792,#803),#781,.T.);
#805=CARTESIAN_POINT('',(0.,0.,1.5367));
#806=DIRECTION('',(0.,0.,1.));
#807=DIRECTION('',(1.,0.,0.));
#808=AXIS2_PLACEMENT_3D('',#805,#806,#807);
#809=TOROIDAL_SURFACE('',#808,22.3774,2.54);
#810=ORIENTED_EDGE('',*,*,#608,.F.);
#811=EDGE_LOOP('',(#810));
#812=FACE_BOUND('',#811,.T.);
#813=ORIENTED_EDGE('',*,*,#256,.F.);
#814=EDGE_LOOP('',(#813));
#815=FACE_BOUND('',#814,.T.);
#816=ADVANCED_FACE('F457',(#812,#815),#809,.T.);
#817=CARTESIAN_POINT('',(0.,0.,1.6383));
#818=DIRECTION('',(0.,0.,1.));
#819=DIRECTION('',(1.,0.,0.));
#820=AXIS2_PLACEMENT_3D('',#817,#818,#819);
#821=TOROIDAL_SURFACE('',#820,21.4503,0.635);
#822=ORIENTED_EDGE('',*,*,#101,.F.);
#823=EDGE_LOOP('',(#822));
#824=FACE_BOUND('',#823,.T.);
#825=ORIENTED_EDGE('',*,*,#800,.F.);
#826=EDGE_LOOP('',(#825));
#827=FACE_BOUND('',#826,.T.);
#828=ADVANCED_FACE('F460',(#824,#827),#821,.F.);
#829=CARTESIAN_POINT('',(-16.7052819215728,-23.5423664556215,-0.4953));
#830=DIRECTION('',(0.815543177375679,-0.578696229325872,0.));
#831=DIRECTION('',(0.578696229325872,0.815543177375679,0.));
#832=AXIS2_PLACEMENT_3D('',#829,#830,#831);
#833=CYLINDRICAL_SURFACE('',#832,0.508);
#834=CARTESIAN_POINT('',(-40.2493417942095,-6.83588291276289,-0.4953));
#835=DIRECTION('',(-0.815543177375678,0.578696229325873,0.));
#836=DIRECTION('',(-0.578696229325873,-0.815543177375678,0.));
#837=AXIS2_PLACEMENT_3D('',#834,#835,#836);
#838=CIRCLE('',#837,0.508);
#839=EDGE_CURVE('E396',#229,#414,#838,.T.);
#840=ORIENTED_EDGE('',*,*,#839,.F.);
#841=ORIENTED_EDGE('',*,*,#230,.F.);
#842=CARTESIAN_POINT('',(-16.7052819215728,-23.5423664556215,-0.4953));
#843=DIRECTION('',(0.81554317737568,-0.578696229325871,0.));
#844=DIRECTION('',(0.578696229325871,0.81554317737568,0.));
#845=AXIS2_PLACEMENT_3D('',#842,#843,#844);
#846=CIRCLE('',#845,0.508);
#847=EDGE_CURVE('E236',#446,#221,#846,.T.);
#848=ORIENTED_EDGE('',*,*,#847,.F.);
#849=ORIENTED_EDGE('',*,*,#447,.F.);
#850=EDGE_LOOP('',(#840,#841,#848,#849));
#851=FACE_BOUND('',#850,.T.);
#852=ADVANCED_FACE('F523',(#851),#833,.T.);
#853=CARTESIAN_POINT('',(0.,0.,-0.4953));
#854=DIRECTION('',(0.,0.,1.));
#855=DIRECTION('',(1.,0.,0.));
#856=AXIS2_PLACEMENT_3D('',#853,#854,#855);
#857=TOROIDAL_SURFACE('',#856,28.8671,0.508);
#858=ORIENTED_EDGE('',*,*,#847,.T.);
#859=ORIENTED_EDGE('',*,*,#222,.F.);
#860=CARTESIAN_POINT('',(16.7052819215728,-23.5423664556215,-0.4953));
#861=DIRECTION('',(0.81554317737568,0.578696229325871,0.));
#862=DIRECTION('',(-0.578696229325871,0.81554317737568,0.));
#863=AXIS2_PLACEMENT_3D('',#860,#861,#862);
#864=CIRCLE('',#863,0.508);
#865=EDGE_CURVE('E393',#478,#212,#864,.T.);
#866=ORIENTED_EDGE('',*,*,#865,.F.);
#867=ORIENTED_EDGE('',*,*,#479,.F.);
#868=EDGE_LOOP('',(#858,#859,#866,#867));
#869=FACE_BOUND('',#868,.T.);
#870=ADVANCED_FACE('F549',(#869),#857,.T.);
#871=CARTESIAN_POINT('',(-35.39871,0.,-0.4953));
#872=DIRECTION('',(0.,0.,1.));
#873=DIRECTION('',(1.,0.,0.));
#874=AXIS2_PLACEMENT_3D('',#871,#872,#873);
#875=TOROIDAL_SURFACE('',#874,8.382,0.508);
#876=ORIENTED_EDGE('',*,*,#839,.T.);
#877=ORIENTED_EDGE('',*,*,#415,.F.);
#878=CARTESIAN_POINT('',(-40.2493417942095,6.83588291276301,-0.4953));
#879=DIRECTION('',(0.815543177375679,0.578696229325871,0.));
#880=DIRECTION('',(-0.578696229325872,0.815543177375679,0.));
#881=AXIS2_PLACEMENT_3D('',#878,#879,#880);
#882=CIRCLE('',#881,0.508);
#883=EDGE_CURVE('E390',#238,#382,#882,.T.);
#884=ORIENTED_EDGE('',*,*,#883,.F.);
#885=ORIENTED_EDGE('',*,*,#239,.F.);
#886=EDGE_LOOP('',(#876,#877,#884,#885));
#887=FACE_BOUND('',#886,.T.);
#888=ADVANCED_FACE('F545',(#887),#875,.T.);
#889=CARTESIAN_POINT('',(16.7052819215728,-23.5423664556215,-0.4953));
#890=DIRECTION('',(0.81554317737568,0.578696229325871,0.));
#891=DIRECTION('',(-0.578696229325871,0.81554317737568,0.));
#892=AXIS2_PLACEMENT_3D('',#889,#890,#891);
#893=CYLINDRICAL_SURFACE('',#892,0.508);
#894=ORIENTED_EDGE('',*,*,#865,.T.);
#895=ORIENTED_EDGE('',*,*,#213,.F.);
#896=CARTESIAN_POINT('',(40.2493417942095,-6.83588291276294,-0.4953));
#897=DIRECTION('',(0.815543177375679,0.578696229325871,0.));
#898=DIRECTION('',(-0.578696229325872,0.815543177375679,0.));
#899=AXIS2_PLACEMENT_3D('',#896,#897,#898);
#900=CIRCLE('',#899,0.508);
#901=EDGE_CURVE('E387',#510,#204,#900,.T.);
#902=ORIENTED_EDGE('',*,*,#901,.F.);
#903=ORIENTED_EDGE('',*,*,#511,.F.);
#904=EDGE_LOOP('',(#894,#895,#902,#903));
#905=FACE_BOUND('',#904,.T.);
#906=ADVANCED_FACE('F541',(#905),#893,.T.);
#907=CARTESIAN_POINT('',(-16.7052819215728,23.5423664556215,-0.4953));
#908=DIRECTION('',(-0.81554317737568,-0.578696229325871,0.));
#909=DIRECTION('',(0.578696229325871,-0.81554317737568,0.));
#910=AXIS2_PLACEMENT_3D('',#907,#908,#909);
#911=CYLINDRICAL_SURFACE('',#910,0.508);
#912=ORIENTED_EDGE('',*,*,#883,.T.);
#913=ORIENTED_EDGE('',*,*,#383,.F.);
#914=CARTESIAN_POINT('',(-16.7052819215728,23.5423664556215,-0.4953));
#915=DIRECTION('',(0.81554317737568,0.578696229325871,0.));
#916=DIRECTION('',(-0.578696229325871,0.81554317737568,0.));
#917=AXIS2_PLACEMENT_3D('',#914,#915,#916);
#918=CIRCLE('',#917,0.508);
#919=EDGE_CURVE('E384',#185,#350,#918,.T.);
#920=ORIENTED_EDGE('',*,*,#919,.F.);
#921=ORIENTED_EDGE('',*,*,#245,.F.);
#922=EDGE_LOOP('',(#912,#913,#920,#921));
#923=FACE_BOUND('',#922,.T.);
#924=ADVANCED_FACE('F537',(#923),#911,.T.);
#925=CARTESIAN_POINT('',(35.39871,0.,-0.4953));
#926=DIRECTION('',(0.,0.,1.));
#927=DIRECTION('',(1.,0.,0.));
#928=AXIS2_PLACEMENT_3D('',#925,#926,#927);
#929=TOROIDAL_SURFACE('',#928,8.38200000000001,0.508);
#930=ORIENTED_EDGE('',*,*,#901,.T.);
#931=ORIENTED_EDGE('',*,*,#205,.F.);
#932=CARTESIAN_POINT('',(40.2493417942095,6.83588291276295,-0.4953));
#933=DIRECTION('',(-0.815543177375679,0.578696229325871,0.));
#934=DIRECTION('',(-0.578696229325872,-0.815543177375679,0.));
#935=AXIS2_PLACEMENT_3D('',#932,#933,#934);
#936=CIRCLE('',#935,0.508);
#937=EDGE_CURVE('E381',#542,#195,#936,.T.);
#938=ORIENTED_EDGE('',*,*,#937,.F.);
#939=ORIENTED_EDGE('',*,*,#543,.F.);
#940=EDGE_LOOP('',(#930,#931,#938,#939));
#941=FACE_BOUND('',#940,.T.);
#942=ADVANCED_FACE('F533',(#941),#929,.T.);
#943=CARTESIAN_POINT('',(0.,0.,-0.4953));
#944=DIRECTION('',(0.,0.,1.));
#945=DIRECTION('',(1.,0.,0.));
#946=AXIS2_PLACEMENT_3D('',#943,#944,#945);
#947=TOROIDAL_SURFACE('',#946,28.8671,0.508);
#948=ORIENTED_EDGE('',*,*,#919,.T.);
#949=ORIENTED_EDGE('',*,*,#351,.F.);
#950=CARTESIAN_POINT('',(16.7052819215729,23.5423664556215,-0.4953));
#951=DIRECTION('',(0.815543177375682,-0.578696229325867,0.));
#952=DIRECTION('',(0.578696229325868,0.815543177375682,0.));
#953=AXIS2_PLACEMENT_3D('',#950,#951,#952);
#954=CIRCLE('',#953,0.508);
#955=EDGE_CURVE('E379',#187,#341,#954,.T.);
#956=ORIENTED_EDGE('',*,*,#955,.F.);
#957=ORIENTED_EDGE('',*,*,#188,.F.);
#958=EDGE_LOOP('',(#948,#949,#956,#957));
#959=FACE_BOUND('',#958,.T.);
#960=ADVANCED_FACE('F529',(#959),#947,.T.);
#961=CARTESIAN_POINT('',(16.7052819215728,23.5423664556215,-0.4953));
#962=DIRECTION('',(-0.81554317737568,0.578696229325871,0.));
#963=DIRECTION('',(-0.578696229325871,-0.81554317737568,0.));
#964=AXIS2_PLACEMENT_3D('',#961,#962,#963);
#965=CYLINDRICAL_SURFACE('',#964,0.508);
#966=ORIENTED_EDGE('',*,*,#937,.T.);
#967=ORIENTED_EDGE('',*,*,#196,.F.);
#968=ORIENTED_EDGE('',*,*,#955,.T.);
#969=ORIENTED_EDGE('',*,*,#573,.F.);
#970=EDGE_LOOP('',(#966,#967,#968,#969));
#971=FACE_BOUND('',#970,.T.);
#972=ADVANCED_FACE('F525',(#971),#965,.T.);
#973=CARTESIAN_POINT('',(-16.7052819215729,-23.5423664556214,0.4953));
#974=DIRECTION('',(-0.815543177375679,0.578696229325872,0.));
#975=DIRECTION('',(-0.578696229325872,-0.815543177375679,0.));
#976=AXIS2_PLACEMENT_3D('',#973,#974,#975);
#977=CYLINDRICAL_SURFACE('',#976,0.508);
#978=CARTESIAN_POINT('',(-40.2493417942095,-6.83588291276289,0.4953));
#979=DIRECTION('',(-0.815543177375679,0.578696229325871,0.));
#980=DIRECTION('',(-0.578696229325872,-0.815543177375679,0.));
#981=AXIS2_PLACEMENT_3D('',#978,#979,#980);
#982=CIRCLE('',#981,0.508);
#983=EDGE_CURVE('E417',#422,#66,#982,.T.);
#984=ORIENTED_EDGE('',*,*,#983,.F.);
#985=ORIENTED_EDGE('',*,*,#461,.F.);
#986=CARTESIAN_POINT('',(-16.7052819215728,-23.5423664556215,0.4953));
#987=DIRECTION('',(0.815543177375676,-0.578696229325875,0.));
#988=DIRECTION('',(0.578696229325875,0.815543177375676,0.));
#989=AXIS2_PLACEMENT_3D('',#986,#987,#988);
#990=CIRCLE('',#989,0.508);
#991=EDGE_CURVE('E382',#74,#454,#990,.T.);
#992=ORIENTED_EDGE('',*,*,#991,.F.);
#993=ORIENTED_EDGE('',*,*,#75,.F.);
#994=EDGE_LOOP('',(#984,#985,#992,#993));
#995=FACE_BOUND('',#994,.T.);
#996=ADVANCED_FACE('F528',(#995),#977,.T.);
#997=CARTESIAN_POINT('',(0.,0.,0.4953));
#998=DIRECTION('',(0.,0.,1.));
#999=DIRECTION('',(1.,0.,0.));
#1000=AXIS2_PLACEMENT_3D('',#997,#998,#999);
#1001=TOROIDAL_SURFACE('',#1000,28.8671,0.508);
#1002=ORIENTED_EDGE('',*,*,#991,.T.);
#1003=ORIENTED_EDGE('',*,*,#494,.F.);
#1004=CARTESIAN_POINT('',(16.7052819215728,-23.5423664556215,0.4953));
#1005=DIRECTION('',(0.81554317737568,0.578696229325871,0.));
#1006=DIRECTION('',(-0.578696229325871,0.81554317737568,0.));
#1007=AXIS2_PLACEMENT_3D('',#1004,#1005,#1006);
#1008=CIRCLE('',#1007,0.508);
#1009=EDGE_CURVE('E414',#83,#486,#1008,.T.);
#1010=ORIENTED_EDGE('',*,*,#1009,.F.);
#1011=ORIENTED_EDGE('',*,*,#84,.F.);
#1012=EDGE_LOOP('',(#1002,#1003,#1010,#1011));
#1013=FACE_BOUND('',#1012,.T.);
#1014=ADVANCED_FACE('F579',(#1013),#1001,.T.);
#1015=CARTESIAN_POINT('',(-35.39871,0.,0.4953));
#1016=DIRECTION('',(0.,0.,1.));
#1017=DIRECTION('',(1.,0.,0.));
#1018=AXIS2_PLACEMENT_3D('',#1015,#1016,#1017);
#1019=TOROIDAL_SURFACE('',#1018,8.382,0.508);
#1020=ORIENTED_EDGE('',*,*,#983,.T.);
#1021=ORIENTED_EDGE('',*,*,#67,.F.);
#1022=CARTESIAN_POINT('',(-40.2493417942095,6.83588291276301,0.4953));
#1023=DIRECTION('',(0.815543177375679,0.578696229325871,0.));
#1024=DIRECTION('',(-0.578696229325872,0.815543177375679,0.));
#1025=AXIS2_PLACEMENT_3D('',#1022,#1023,#1024);
#1026=CIRCLE('',#1025,0.508);
#1027=EDGE_CURVE('E411',#390,#57,#1026,.T.);
#1028=ORIENTED_EDGE('',*,*,#1027,.F.);
#1029=ORIENTED_EDGE('',*,*,#430,.F.);
#1030=EDGE_LOOP('',(#1020,#1021,#1028,#1029));
#1031=FACE_BOUND('',#1030,.T.);
#1032=ADVANCED_FACE('F575',(#1031),#1019,.T.);
#1033=CARTESIAN_POINT('',(16.7052819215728,-23.5423664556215,0.4953));
#1034=DIRECTION('',(-0.81554317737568,-0.578696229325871,0.));
#1035=DIRECTION('',(0.578696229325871,-0.81554317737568,0.));
#1036=AXIS2_PLACEMENT_3D('',#1033,#1034,#1035);
#1037=CYLINDRICAL_SURFACE('',#1036,0.508);
#1038=ORIENTED_EDGE('',*,*,#1009,.T.);
#1039=ORIENTED_EDGE('',*,*,#525,.F.);
#1040=CARTESIAN_POINT('',(40.2493417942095,-6.83588291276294,0.4953));
#1041=DIRECTION('',(0.815543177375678,0.578696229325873,0.));
#1042=DIRECTION('',(-0.578696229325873,0.815543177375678,0.));
#1043=AXIS2_PLACEMENT_3D('',#1040,#1041,#1042);
#1044=CIRCLE('',#1043,0.508);
#1045=EDGE_CURVE('E408',#30,#518,#1044,.T.);
#1046=ORIENTED_EDGE('',*,*,#1045,.F.);
#1047=ORIENTED_EDGE('',*,*,#90,.F.);
#1048=EDGE_LOOP('',(#1038,#1039,#1046,#1047));
#1049=FACE_BOUND('',#1048,.T.);
#1050=ADVANCED_FACE('F571',(#1049),#1037,.T.);
#1051=CARTESIAN_POINT('',(-16.7052819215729,23.5423664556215,0.4953));
#1052=DIRECTION('',(0.81554317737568,0.578696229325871,0.));
#1053=DIRECTION('',(-0.578696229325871,0.81554317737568,0.));
#1054=AXIS2_PLACEMENT_3D('',#1051,#1052,#1053);
#1055=CYLINDRICAL_SURFACE('',#1054,0.508);
#1056=ORIENTED_EDGE('',*,*,#1027,.T.);
#1057=ORIENTED_EDGE('',*,*,#58,.F.);
#1058=CARTESIAN_POINT('',(-16.7052819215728,23.5423664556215,0.4953));
#1059=DIRECTION('',(0.81554317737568,0.578696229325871,0.));
#1060=DIRECTION('',(-0.578696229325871,0.81554317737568,0.));
#1061=AXIS2_PLACEMENT_3D('',#1058,#1059,#1060);
#1062=CIRCLE('',#1061,0.508);
#1063=EDGE_CURVE('E405',#358,#49,#1062,.T.);
#1064=ORIENTED_EDGE('',*,*,#1063,.F.);
#1065=ORIENTED_EDGE('',*,*,#397,.F.);
#1066=EDGE_LOOP('',(#1056,#1057,#1064,#1065));
#1067=FACE_BOUND('',#1066,.T.);
#1068=ADVANCED_FACE('F567',(#1067),#1055,.T.);
#1069=CARTESIAN_POINT('',(35.39871,0.,0.4953));
#1070=DIRECTION('',(0.,0.,1.));
#1071=DIRECTION('',(1.,0.,0.));
#1072=AXIS2_PLACEMENT_3D('',#1069,#1070,#1071);
#1073=TOROIDAL_SURFACE('',#1072,8.38200000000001,0.508);
#1074=ORIENTED_EDGE('',*,*,#1045,.T.);
#1075=ORIENTED_EDGE('',*,*,#558,.F.);
#1076=CARTESIAN_POINT('',(40.2493417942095,6.83588291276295,0.4953));
#1077=DIRECTION('',(-0.815543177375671,0.578696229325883,0.));
#1078=DIRECTION('',(-0.578696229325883,-0.815543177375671,0.));
#1079=AXIS2_PLACEMENT_3D('',#1076,#1077,#1078);
#1080=CIRCLE('',#1079,0.508);
#1081=EDGE_CURVE('E403',#32,#550,#1080,.T.);
#1082=ORIENTED_EDGE('',*,*,#1081,.F.);
#1083=ORIENTED_EDGE('',*,*,#33,.F.);
#1084=EDGE_LOOP('',(#1074,#1075,#1082,#1083));
#1085=FACE_BOUND('',#1084,.T.);
#1086=ADVANCED_FACE('F563',(#1085),#1073,.T.);
#1087=CARTESIAN_POINT('',(0.,0.,0.4953));
#1088=DIRECTION('',(0.,0.,1.));
#1089=DIRECTION('',(1.,0.,0.));
#1090=AXIS2_PLACEMENT_3D('',#1087,#1088,#1089);
#1091=TOROIDAL_SURFACE('',#1090,28.8671,0.508);
#1092=ORIENTED_EDGE('',*,*,#1063,.T.);
#1093=ORIENTED_EDGE('',*,*,#50,.F.);
#1094=CARTESIAN_POINT('',(16.7052819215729,23.5423664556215,0.4953));
#1095=DIRECTION('',(0.81554317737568,-0.578696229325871,0.));
#1096=DIRECTION('',(0.578696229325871,0.81554317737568,0.));
#1097=AXIS2_PLACEMENT_3D('',#1094,#1095,#1096);
#1098=CIRCLE('',#1097,0.508);
#1099=EDGE_CURVE('E401',#339,#40,#1098,.T.);
#1100=ORIENTED_EDGE('',*,*,#1099,.F.);
#1101=ORIENTED_EDGE('',*,*,#366,.F.);
#1102=EDGE_LOOP('',(#1092,#1093,#1100,#1101));
#1103=FACE_BOUND('',#1102,.T.);
#1104=ADVANCED_FACE('F559',(#1103),#1091,.T.);
#1105=CARTESIAN_POINT('',(16.7052819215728,23.5423664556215,0.4953));
#1106=DIRECTION('',(0.81554317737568,-0.578696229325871,0.));
#1107=DIRECTION('',(0.578696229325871,0.81554317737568,0.));
#1108=AXIS2_PLACEMENT_3D('',#1105,#1106,#1107);
#1109=CYLINDRICAL_SURFACE('',#1108,0.508);
#1110=ORIENTED_EDGE('',*,*,#1081,.T.);
#1111=ORIENTED_EDGE('',*,*,#580,.F.);
#1112=ORIENTED_EDGE('',*,*,#1099,.T.);
#1113=ORIENTED_EDGE('',*,*,#41,.F.);
#1114=EDGE_LOOP('',(#1110,#1111,#1112,#1113));
#1115=FACE_BOUND('',#1114,.T.);
#1116=ADVANCED_FACE('F435',(#1115),#1109,.T.);
#1117=CARTESIAN_POINT('',(0.,0.,4.4831));
#1118=DIRECTION('',(0.,0.,1.));
#1119=DIRECTION('',(1.,0.,0.));
#1120=AXIS2_PLACEMENT_3D('',#1117,#1118,#1119);
#1121=TOROIDAL_SURFACE('',#1120,20.6121,0.2032);
#1122=ORIENTED_EDGE('',*,*,#789,.F.);
#1123=EDGE_LOOP('',(#1122));
#1124=FACE_BOUND('',#1123,.T.);
#1125=ORIENTED_EDGE('',*,*,#761,.F.);
#1126=EDGE_LOOP('',(#1125));
#1127=FACE_BOUND('',#1126,.T.);
#1128=ADVANCED_FACE('F432',(#1124,#1127),#1121,.T.);
#1129=CARTESIAN_POINT('',(0.,0.,4.4831));
#1130=DIRECTION('',(0.,0.,1.));
#1131=DIRECTION('',(1.,0.,0.));
#1132=AXIS2_PLACEMENT_3D('',#1129,#1130,#1131);
#1133=TOROIDAL_SURFACE('',#1132,20.0406,0.2032);
#1134=ORIENTED_EDGE('',*,*,#772,.F.);
#1135=EDGE_LOOP('',(#1134));
#1136=FACE_BOUND('',#1135,.T.);
#1137=ORIENTED_EDGE('',*,*,#597,.F.);
#1138=EDGE_LOOP('',(#1137));
#1139=FACE_BOUND('',#1138,.T.);
#1140=ADVANCED_FACE('F44',(#1136,#1139),#1133,.T.);
#1141=CLOSED_SHELL('',(#173,#328,#370,#401,#434,#465,#498,#529,#562,#584,#612,#634,#651,#668,
#680,#702,#719,#736,#748,#776,#804,#816,#828,#852,#870,#888,#906,#924,#942,#960,#972,#996,#1014,
#1032,#1050,#1068,#1086,#1104,#1116,#1128,#1140));
#1142=MANIFOLD_SOLID_BREP('B2',#1141);
#1143=ADVANCED_BREP_SHAPE_REPRESENTATION('',(#18,#1142),#14);
#1144=SHAPE_DEFINITION_REPRESENTATION(#9,#1143);
ENDSEC;
END-ISO-10303-21;
